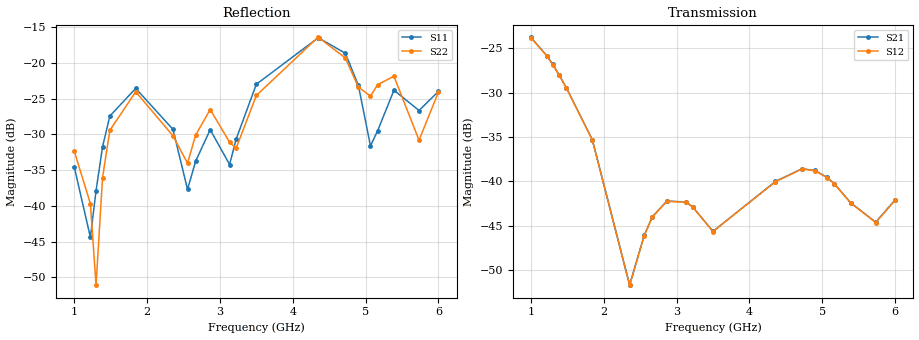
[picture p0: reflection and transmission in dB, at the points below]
!Agilent Technologies,E8364B,MY43040528,A.07.50.67
!Agilent E8364B: A.07.50.67
!Date: Sunday, March 01, 2026 22:26:50
!Correction: S11(Full 2 Port(1,2))
!S21(Full 2 Port(1,2))
!S12(Full 2 Port(1,2))
!S22(Full 2 Port(1,2))
!S2P File: Measurements: S11, S21, S12, S22:
# Hz S  dB  R 50
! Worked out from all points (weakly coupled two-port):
!   451 points, 1 GHz to 6 GHz, reference 50 ohm
!   highest |S21| = -23.75 dB at 1 GHz (marker M1); lowest = -51.7 dB at 2.356 GHz (marker M2)
!   lowest |S11| = -44.4 dB at 1.222 GHz (marker M3), VSWR 1.01, Z = 50.3 - j0.537 ohm
!   |S11| at or under -10 dB: start of sweep to end of sweep
!   |S22| runs from -51.1 to -16.4 dB; largest |S21 - S12| = 0.00023
!   S11 on the Smith chart (normalised r, x): 1 GHz: 1.04, +0.01; 4.356 GHz: 1.20, -0.26; 6 GHz: 0.96, -0.12
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1e9  -34.53 12.4  -23.75 154.9  -23.78 155.0  -32.33 -14.5
1.222222e9  -44.41 -62.6  -25.85 28.3  -25.88 28.3  -39.70 -38.9
1.3e9  -37.87 -130.8  -26.79 -15.6  -26.83 -15.5  -51.10 -125.4
1.388889e9  -31.75 -165.8  -28.01 -65.0  -28.04 -64.9  -36.06 117.9
1.488889e9  -27.45 162.6  -29.48 -119.5  -29.50 -119.5  -29.45 83.7
1.844444e9  -23.57 83.0  -35.33 51.1  -35.36 51.2  -24.05 -9.0
2.355556e9  -29.31 13.2  -51.72 -148.9  -51.73 -149.0  -30.21 -92.3
2.555556e9  -37.71 32.2  -46.12 157.1  -46.16 157.0  -34.04 -70.3
2.666667e9  -33.78 67.4  -44.02 103.9  -44.05 103.9  -30.12 -64.1
2.866667e9  -29.35 46.7  -42.24 1.1  -42.27 1.2  -26.53 -101.1
3.133333e9  -34.23 56.6  -42.34 -138.2  -42.37 -138.2  -31.11 -138.2
3.222222e9  -30.70 75.6  -42.90 176.3  -42.94 176.4  -31.96 -122.0
3.5e9  -23.00 49.5  -45.66 46.7  -45.68 46.8  -24.57 -132.6
4.344444e9  -16.53 -44.2  -40.11 23.2  -40.13 23.2  -16.44 111.6
4.355556e9  -16.52 -45.9  -40.02 17.3  -40.06 17.3  -16.46 109.4
4.722222e9  -18.66 -106.6  -38.59 174.0  -38.62 174.1  -19.32 42.7
4.9e9  -23.13 -133.8  -38.78 71.2  -38.82 71.2  -23.38 25.0
5.066667e9  -31.61 -119.5  -39.56 -27.4  -39.59 -27.4  -24.66 34.4
5.166667e9  -29.48 -78.0  -40.28 -87.6  -40.32 -87.6  -23.04 30.4
5.388889e9  -23.83 -95.1  -42.42 132.5  -42.45 132.6  -21.88 -8.0
5.733333e9  -26.67 -111.3  -44.62 -113.0  -44.66 -113.0  -30.82 -25.8
6e9  -23.99 -104.9  -42.09 59.5  -42.14 59.5  -24.09 -20.7
